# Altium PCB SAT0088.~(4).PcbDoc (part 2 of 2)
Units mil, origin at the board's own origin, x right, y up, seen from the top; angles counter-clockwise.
Board outline 1614.17 x 1181.1 mil, 4 copper layers (Top Layer, InternalPlane1, POWER, Bottom Layer), stack 59 mil thick; 84 components, 49 nets, 273 pads, 217 vias.
Unrouted connection lines stored in the file: 3.

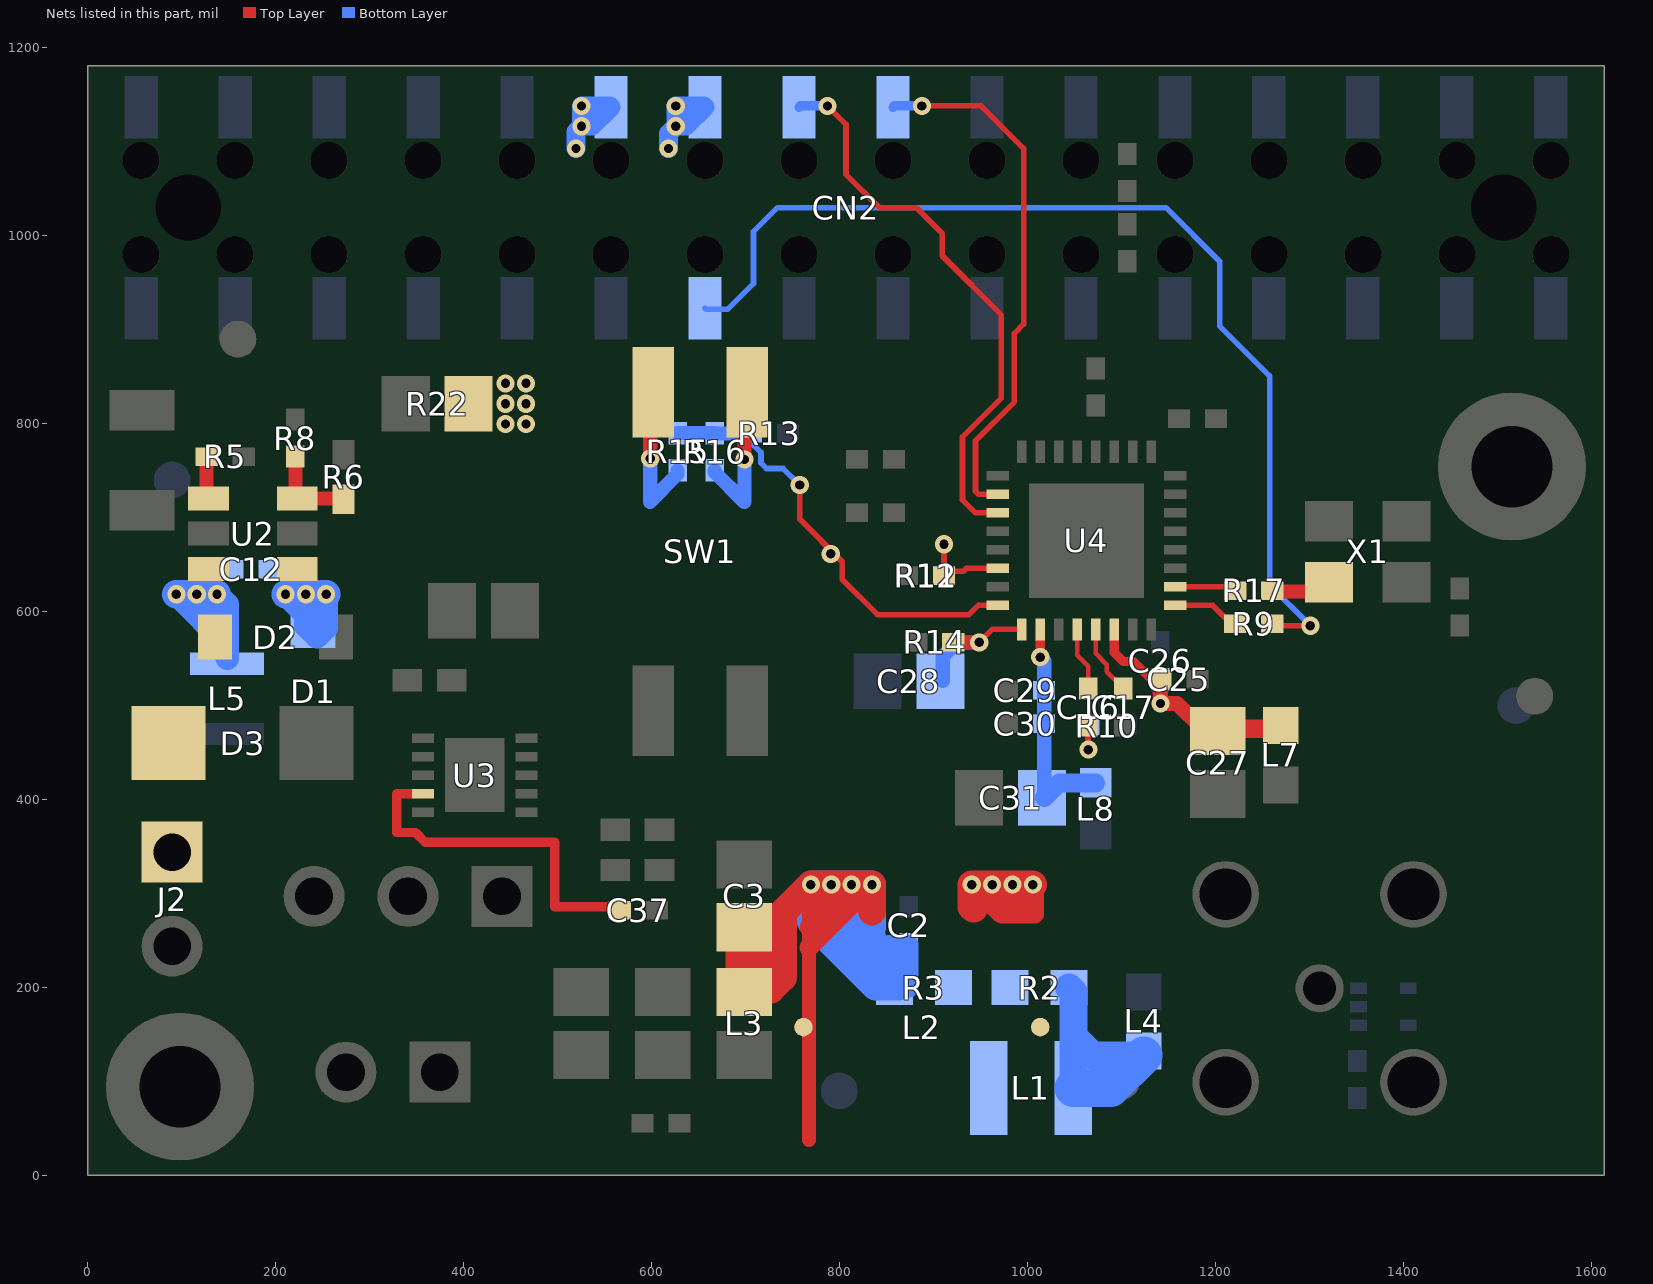
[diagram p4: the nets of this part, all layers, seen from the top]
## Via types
v1: diameter 19.29, hole 9.84, Top Layer to Bottom Layer, tented both sides, 208 vias
v2: diameter 19.68, hole 7.87, Top Layer to Bottom Layer, 5 vias
v3: diameter 19.68, hole 7.87, Top Layer to Bottom Layer, tented top, 4 vias

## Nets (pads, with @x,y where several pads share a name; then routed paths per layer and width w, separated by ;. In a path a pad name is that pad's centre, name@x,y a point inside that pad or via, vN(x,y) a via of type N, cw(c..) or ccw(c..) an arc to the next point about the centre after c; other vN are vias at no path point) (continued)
NetC2_1: C2.1 C3.1 L2.2 L3.1 R3.1 | length 1504.5
  Top Layer w15: 767.72,37.8 767.72,242.52 767.72,264.17 767.72,285.83 767.72,307.48 v1(769.68,309.45)
  Top Layer w20: 767.72,242.52 v1(834.65,309.45) ; 767.72,264.17 v1(812.99,309.45) ; 767.72,285.83 v1(791.34,309.45)
  Top Layer w30: L3.1@698.82,197.81 L3.1@726.94,197.81 ; v1@767.72,307.48 740.16,279.92 ; v1(769.68,309.45) v1(791.34,309.45) v1(812.99,309.45) v1(834.65,309.45) 834.65,281 ; L3.1@726.94,197.81 726.94,233.51 698.82,261.64 721.87,261.64 740.16,279.92 ; L3.1@726.94,197.81 740.16,211.02 740.16,279.92
  Top Layer w40: L3.1@698.82,197.81 C3.1@698.82,261.64
  Bottom Layer w20: 834.65,238.64 842.15,246.14 834.65,253.64 ; 852.39,220.9 874.02,242.52 C2.1@874.02,246.14 ; 852.68,246.14 C2.1@874.02,246.14 ; R3.1@874.07,199.21 874.07,246.08 C2.1@874.02,246.14
  Bottom Layer w30: 834.65,253.64 834.65,238.64 ; 834.65,264.17 v1(834.65,309.45) v1(812.99,309.45) ; 791.34,248.43 v1(791.34,309.45) ; 791.34,248.43 769.68,270.08 v1(769.68,309.45) v1(791.34,309.45) ; 791.34,248.43 838.58,201.18 862.69,201.18 867.4,205.89 852.39,220.9 834.65,238.64 ; v1(791.34,309.45) v1(812.99,309.45) ; v1(812.99,309.45) 812.99,260.3 834.65,238.64
NetC12_1: C12.1 D1.1 U2.1 | length 202
  Bottom Layer w25: v1(210.63,618.5) D1.1@232.28,596.85 ; v1(232.28,618.5) D1.1@232.28,596.85 ; v1(253.94,618.5) 253.94,583.07 D1.1@244.09,573.23 ; D1.1@232.28,596.85 232.28,585.04 D1.1@244.09,573.23 ; D1.1@232.28,596.85 244.09,585.04 D1.1@244.09,573.23
  Bottom Layer w30: v1(210.63,618.5) v1(232.28,618.5) v1(253.94,618.5)
NetC12_2: C12.2 D2.1 L5.1 U2.6 | length 241.7
  Top Layer w25: D2.1@137.8,571.26 D2.1@137.8,575.2
  Bottom Layer w25: v1(94.49,618.5) 148.43,564.57 ; v1(116.14,618.5) 148.43,586.22 ; v1(137.8,618.5) 148.43,607.87 148.43,586.22 ; L5.1@148.43,550.39 148.43,564.57 ; 148.43,564.57 148.43,586.22
  Bottom Layer w30: v1(94.49,618.5) v1(116.14,618.5) v1(137.8,618.5)
NetC16_1: C16.1 R10.1 | length 50.6
  Top Layer w6: v1(1064.96,453.15) C16.1@1064.96,478.43
  Bottom Layer w6: v1(1064.96,453.15) R10.1@1064.96,478.43
NetC16_2: C16.2 U4.12 | length 67.6
  Top Layer w5: U4.12@1053.15,581.1 1053.15,553.54 1064.96,541.73 C16.2@1064.96,518.43
NetC17_2: C17.2 U4.13 | length 74.9
  Top Layer w5: U4.13@1072.83,581.1 1072.83,555.51 1084.65,543.7 1084.65,536.14 C17.2@1102.36,518.43
NetC25_1: C25.1 C26.1 C27.1 L7.1 U4.14 | length 275.7
  Top Layer w9.84: U4.14@1092.52,581.1 1092.52,556.48 1102,547 1112.84,547 1131.89,527.95 C25.1@1141.42,527.95
  Top Layer w16: C25.1@1141.42,527.95 1141.42,502.68 v1(1141.73,502.36) 1159.45,502.36 1186.44,475.37 C27.1@1202.76,475.37
  Top Layer w20: C27.1@1202.76,475.37 1269.06,475.37 L7.1@1269.68,474.74
  Bottom Layer w15: v1(1141.73,502.36) C26.1@1141.73,527.64
NetC28_1: C28.1 R14.2 U4.9 | length 149.5
  Top Layer w6: v1(948.82,567.32) 962.6,581.1 U4.9@994.09,581.1
  Top Layer w15: R14.2@921.57,567.32 v1(948.82,567.32)
  Bottom Layer w15: C28.1@910.02,525.98 910.02,552.14 925.2,567.32 v1(948.82,567.32)
NetC29_1: C29.1 C30.1 C31.1 L8.1 U4.10 | length 242
  Top Layer w9.84: v1(1013.78,551.57) U4.10@1013.78,581.1
  Bottom Layer w15: v1(1013.78,551.57) 1018.03,547.32 1018.03,402.22 C31.1@1018.28,401.97
  Bottom Layer w20: C31.1@1018.28,401.97 1020.28,403.97 1033.97,417.66 L8.1@1072.83,417.72
NetC37_2: C37.2 U3.4 | length 376.9
  Top Layer w10: U3.4@355.88,406.31 329.31,406.31 329,406 329,365 349,365 359.31,354.69 494,354.69 ; 497,354.69 497,286 562.31,286 C37.2@566.31,282
NetCN2_19: CN2.19 CN2.21 R22.2 | length 239.4
  Bottom Layer w20: v1(519.68,1092.91) 519.68,1110.63 v1(525.59,1116.54) ; v1(618.11,1092.91) 618.11,1108.66 v1(625.98,1116.54) ; v1(525.59,1116.54) v1(525.59,1138.19) 555.82,1138.19 CN2.21@557.09,1136.92 536.7,1116.54 v1(525.59,1116.54) ; v1(625.98,1116.54) v1(625.98,1138.19) 655.82,1138.19 CN2.19@657.09,1136.92 636.7,1116.54 v1(625.98,1116.54)
  other v1: 444.88,799.61 466.54,799.61 444.88,821.26 466.54,821.26 444.88,842.91 466.54,842.91
NetD3_2: D3.2 J2.1 | length 5.3
  Top Layer w50: D3.2@86.26,460 D3.2@90,456.26
NetL1_1: L1.1 L2.1 R2.1 R3.2 | length 281.5
  Top Layer w20: v1(940.94,309.45) 951.77,298.62 972.44,277.95 994.09,277.95 ; v1(962.6,309.45) 994.09,277.95 ; v1(984.25,309.45) 995.08,298.62 1007.87,285.83 ; v1(1005.91,309.45) 1007.87,307.48 1007.87,285.83 ; 994.09,277.95 1007.87,277.95 1007.87,285.83
  Top Layer w30: 943,284 940.94,286.06 v1(940.94,309.45) v1(962.6,309.45) v1(984.25,309.45) v1(1005.91,309.45)
NetL1_2: L1.2 L4.1 R2.2 | length 281.3
  Bottom Layer w30: R2.2@1044.5,200 1049.21,195.28 1049.21,148.03 ; L1.2@1049.21,92.91 1049.21,148.03 ; L4.1@1124.02,127.78 1069.46,127.78 1049.21,148.03
  Bottom Layer w40: L1.2@1049.21,92.91 1088.58,92.91 L4.1@1124.02,127.78
NetR5_2: R5.2 U2.4 | length 45.4
  Top Layer w15: R5.2@126.46,764.96 126.46,720 U2.4@126.77,719.69
NetR6_1: R6.1 R8.1 U2.3 | length 95.3
  Top Layer w15: U2.3@221.26,719.69 221.26,764.65 R8.1@222.6,763.31 ; U2.3@223.24,720.4 R6.1@271.72,720.4
NetR9_2: R9.2 U4.17 | length 58.7
  Top Layer w6: U4.17@1157.48,606.69 1197.31,606.69 R9.2@1210.67,593.33
NetR11_2: R11.2 R12.1 U4.6 | length 127
  Top Layer w6: v1(911.42,671.65) 911.42,638.5 915.91,643 931.98,643 935.04,646.06 U4.6@968.5,646.06
  Bottom Layer w6: v1(911.42,671.65) 911.42,638.5 R12.1@911.73,638.19
NetR13_2: R13.2 R15.2 R16.1 U4.8 | length 469.4
  Top Layer w6: v1(757.87,734.65) 757.87,698.43 803.15,653.15 803.15,634.25 840.55,596.85 937.85,596.85 947.69,606.69 U4.8@968.5,606.69
  Bottom Layer w6: R13.2@705.59,789.76 705.59,779.65 706.31,779.65 716.65,769.31 716.65,758.16 722.44,752.36 740.16,752.36 v1(757.87,734.65)
  Bottom Layer w15: R15.2@627.95,790.08 667.32,790.08 667.64,789.76 R13.2@705.59,789.76
  other v1: 790.8,661.51
NetR15_1: R15.1 SW1.4 | length 158.9
  Top Layer w15: v1(598.82,763) SW1.4@598.82,830.31
  Bottom Layer w15: v1(598.82,763) 598.82,717.32 598.43,716.93 627.95,746.46 R15.1@627.95,750.08
NetR16_2: R16.2 SW1.3 | length 159.8
  Top Layer w15: v1(699,762) SW1.3@699,830.49
  Bottom Layer w15: R16.2@667.32,750.08 667.32,748.43 698.82,716.93 699,717.11 v1(699,762)
NetR17_2: R17.2 X1.3 | length 45
  Top Layer w15: R17.2@1259.91,621.38 X1.3@1304.87,621.38
OSC_48MHZ: R17.1 U4.18 | length 65.6
  Top Layer w6: U4.18@1157.48,626.38 1216.94,626.38 R17.1@1221.32,622
PCLK: CN2.17 U4.3 | length 610.1
  Top Layer w6: v1(787.4,1138.19) 807.09,1118.5 807.09,1065.35 842.52,1029.92 881.89,1029.92 909.45,1002.36 909.45,978.74 972.44,915.75 972.44,827.17 931.1,785.83 931.1,718.9 944.88,705.12 U4.3@968.5,705.12
  Bottom Layer w10: CN2.17@757.09,1136.92 758.35,1138.19 v1(787.4,1138.19)
VSYNC: CN2.15 U4.2 | length 569.2
  Top Layer w6: v1(887.8,1138.19) 950.79,1138.19 996.06,1092.91 996.06,905.91 986.22,896.06 986.22,823.23 944.88,781.89 944.88,728.12 948.2,724.8 U4.2@968.5,724.8
  Bottom Layer w10: CN2.15@857.09,1136.92 858.35,1138.19 v1(887.8,1138.19)
XCLK: CN2.20 R9.1 | length 1117.2
  Top Layer w6: R9.1@1260.68,585.04 v1(1301.18,585.04)
  Bottom Layer w6: CN2.20@657.09,922.92 658.35,921.65 681.1,921.65 708.66,949.21 708.66,1004.33 734.25,1029.92 1147.64,1029.92 1204.72,972.83 1204.72,903.94 1257.87,850.79 1257.87,628.35 v1(1301.18,585.04)
pads on no net: CN2. CN2.11 CN2.25 CN2.26 CN2.27 CN2.28 CN2.29 CN2.30 FID1.1 FID2.1 FID3.1 FID4.1 FID5.1 FID6.1 TR1.2 TR1.5 U3.5 U3.7 U3.8 U4.31 U4.32 X1.1
copper on no net: | length 74.3
  Bottom Layer w10: 332.68,513.86 368.43,513.86 395.67,486.61
  other v3: 412,398.44 392.32,426 431.68,426 412,453.56

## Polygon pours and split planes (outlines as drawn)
DGND on Top Layer "Top Layer, Top-DGND" (solid, remove dead copper, pour order 9): 27.56,25.98 1586.61,25.98 1586.61,1151.97 27.56,1151.97
+5V_EXT on Top Layer "Top Layer-No Net 1" (solid, remove dead copper, pour order 8): 205,495 205,265 285,265 285,500 205,500
NetD3_2 on Top Layer "Top Layer-No Net 1" (solid, remove dead copper, pour order 7): 45,500 45,310 125,310 125,500
DGND on Bottom Layer "Bottom Layer, Bottom-DGND" (solid, remove dead copper, pour order 10): 27.56,25.98 1586.61,25.98 1586.61,1151.97 27.56,1151.97
+3V3 on Bottom Layer "Top Layer-No Net 1" (solid, remove dead copper, pour order 6): 110,480 110,405 245,405 265,425 265,480
DGND on InternalPlane1 (split plane): 1594.08,20.1 20.1,20.1 20.1,1161.01 1594.08,1161.01
NetCN2_19 on POWER (split plane): 655.27,1043.94 507.87,1043.94 505.26,1043.6 502.83,1042.59 500.74,1040.99 499.14,1038.9 498.13,1036.47 497.79,1033.86 497.79,768.35 341.91,768.35 340.8,769.47 340.8,1161.57 655.27,1161.57
+5V on POWER (split plane): 320.62,780.59 320.31,780.9 320.62,780.9
+1V8 on POWER (split plane): 1092.28,774.02 1092.62,771.41 1093.63,768.97 1095.23,766.88 1097.32,765.28 1099.75,764.27 1102.36,763.93 1253.69,763.93 1253.69,557.48 1254.04,554.87 1255.04,552.44 1256.65,550.35 1258.74,548.75 1261.17,547.74 1263.78,547.39 1604.09,547.39 1604.09,10.09 1399.85,10.09 1399.85,317.32 1399.51,319.93 1398.5,322.37 1396.9,324.45 1394.81,326.06 1392.37,327.07 1389.76,327.41 1259.84,327.41 1257.23,327.07 1254.8,326.06 1252.71,324.45 1251.11,322.37 1250.1,319.93 1249.76,317.32 1249.76,276.23 491.1,276.23 491.1,352 490.71,353.95 489.6,355.6 487.95,356.71 486,357.1 393.11,357.1 387.1,363.11 387.1,383.52 389.02,384.99 390.62,387.08 391.63,389.52 391.98,392.13 391.98,654.74 506.73,654.74 509.9,651.57 509.9,454 509.9,401 510.29,399.05 511.4,397.4 513.05,396.29 515,395.9 516.95,396.29 517.87,396.9 560,396.9 561.95,397.29 563.6,398.4 564.71,400.05 565.1,402 565.1,653.89 565.95,654.74 770.83,654.74 772.4,652.71 774.48,651.11 776.92,650.1 779.53,649.76 782.14,650.1 784.57,651.11 786.66,652.71 788.26,654.8 789.27,657.23 789.61,659.84 789.61,669.44 842.52,669.44 845.13,669.78 847.56,670.79 849.65,672.4 851.25,674.48 852.26,676.92 852.61,679.53 852.61,821.26 852.26,823.87 851.25,826.3 849.65,828.39 847.56,829.99 845.13,831 842.52,831.35 807.09,831.35 804.48,831 802.76,830.29 802.04,829.99 799.95,828.39 773.38,801.82 750.24,801.82 750.24,858.42 1092.28,858.42
+3V3 on POWER (split plane): 1596.21,567.57 1273.87,567.57 1273.87,774.02 1273.52,776.63 1272.51,779.06 1270.91,781.15 1268.82,782.75 1266.39,783.76 1263.78,784.1 1112.45,784.1 1112.45,868.5 1112.1,871.11 1111.1,873.55 1109.49,875.64 1107.41,877.24 1104.97,878.25 1102.36,878.59 740.16,878.59 737.55,878.25 735.11,877.24 733.03,875.64 731.42,873.55 730.41,871.11 730.07,868.5 730.07,791.73 730.41,789.12 731.42,786.69 733.03,784.6 735.11,783 737.55,781.99 740.16,781.65 777.56,781.65 780.17,781.99 782.6,783 784.69,784.6 811.26,811.17 832.43,811.17 832.43,689.61 779.53,689.61 776.92,689.27 774.48,688.26 772.4,686.66 770.79,684.57 769.79,682.14 769.44,679.53 769.44,664.94 563.84,664.94 561.89,664.55 560.24,663.45 556.4,659.6 555.29,657.95 554.9,656 554.9,407.1 520.1,407.1 520.1,454 520.1,653.69 519.71,655.64 518.6,657.29 512.45,663.45 510.79,664.55 508.84,664.94 390.58,664.94 389.02,666.97 386.93,668.58 384.5,669.59 381.89,669.93 379.28,669.59 376.85,668.58 374.76,666.97 373.15,664.89 372.15,662.45 371.8,659.84 371.8,659.1 337.11,659.1 332.1,664.11 332.1,747.54 331.94,748.34 333.32,748.53 334.22,748.9 335.12,748.53 337.73,748.18 507.87,748.18 510.48,748.53 512.92,749.53 515.01,751.14 516.61,753.22 517.62,755.66 517.96,758.27 517.96,1023.77 665.35,1023.77 667.96,1024.12 670.4,1025.12 672.49,1026.73 674.09,1028.82 675.1,1031.25 675.44,1033.86 675.44,1161.57 1596.21,1161.57
+5V_LOCAL on POWER (split plane): 320.62,766.17 320.62,765.29 320.62,758.27 320.97,755.66 321.97,753.22 323.51,751.22 323.4,751.14 322.29,749.49 321.9,747.54 321.9,662 322.29,660.05 323.4,658.4 331.4,650.4 333.05,649.29 335,648.9 371.8,648.9 371.8,392.13 372.15,389.52 373.15,387.08 374.76,384.99 376.85,383.39 376.9,383.37 376.9,361 377.29,359.05 378.4,357.4 387.4,348.4 389.05,347.29 391,346.9 480.9,346.9 480.9,270.31 480.26,268.75 479.91,266.14 480.26,263.53 480.9,261.97 480.9,252.1 397.1,252.1 397.1,319 396.71,320.95 395.6,322.6 340.1,378.11 340.1,538 339.71,539.95 338.6,541.6 323.1,557.11 323.1,595 323.1,615 322.71,616.95 321.6,618.6 301.78,638.43 302.66,639.76 303.05,641.71 303.05,689.05 302.66,691 301.56,692.65 299.9,693.76 299.34,693.87 282.05,711.16 282.05,780.9 305.89,780.9
+5V on POWER (split plane): 320.62,791.1 276.95,791.1 275,790.71 273.35,789.6 272.24,787.95 271.85,786 271.85,709.05 272.24,707.1 273.35,705.44 292.85,685.94 292.85,641.71 292.99,641 292.4,640.6 291.29,638.95 290.9,637 291.29,635.05 292.4,633.4 312.9,612.89 312.9,595 312.9,555 313.29,553.05 314.4,551.4 329.9,535.89 329.9,376 330.29,374.05 331.4,372.4 386.9,316.89 386.9,256.1 296.11,256.1 293.1,259.11 293.1,347 292.71,348.95 291.6,350.6 233.75,408.46 234.09,411 234.09,873.91 320.62,873.91
+POC_VOLTAGE on POWER (split plane): 320.62,894.09 229,894.09 226.39,893.74 223.96,892.74 221.87,891.13 220.26,889.04 219.88,888.12 218.96,887.74 216.87,886.13 215.26,884.04 214.26,881.61 213.91,879 213.91,411 214.26,408.39 215.26,405.96 216.87,403.87 218.96,402.27 221.39,401.26 224,400.91 226.54,401.25 282.9,344.89 282.9,257 283.29,255.05 284.4,253.4 290.4,247.4 292.05,246.29 294,245.9 383.12,245.9 383.29,245.05 384.4,243.4 386.05,242.29 388,241.9 480.89,241.9 482.4,240.4 484.05,239.29 486,238.9 487.95,239.29 489.6,240.4 490.71,242.05 491.1,244 491.1,256.06 1259.84,256.06 1262.45,256.4 1264.89,257.41 1266.97,259.01 1268.58,261.1 1269.59,263.53 1269.93,266.14 1269.93,307.24 1379.68,307.24 1379.68,16.38 773.74,15.8 773.71,15.95 772.6,17.6 770.95,18.71 769,19.1 767.05,18.71 765.4,17.6 764.29,15.95 764.26,15.79 332.73,15.39 17.96,16.35 17.96,1161.57 320.62,1161.57

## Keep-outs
Keep-Out Layer:
  text ".Layer_Name" at 577,-858.49 h60

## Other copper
Top Layer:
  rectangle net +POC_VOLTAGE: 149,752 189,802
  rectangle net NetC12_2: 80.32,604.34 127,633
  rectangle net NetC12_2: 104,548 155,661
  rectangle net +POC_VOLTAGE: 494,57 558,156
  rectangle net +POC_VOLTAGE: 667,79 731,155
  rectangle net +POC_VOLTAGE: 580,79 644,156
  rectangle net NetCN2_19: 380,790 480,855
  rectangle net +5V: 265,790 365,855
  rectangle net NetC12_1: 200,605 265,655
  pour cut-out: 735,442 564,442 564,605 562,607 736,607
  pour cut-out: 491,354 613,354 610,495 492,496
  pour cut-out: 1338.58,602.76 1385.83,602.76 1385.83,740.55 1395.67,740.55 1385.83,750.39 1285.43,750.39 1261.81,726.77 1261.81,681.5 1338.58,681.5
  pour cut-out: 980.32,592.91 1145.67,592.91 1145.67,758.27 980.32,758.27
  pour cut-out: 27.56,793.7 27.56,726.77 106.3,726.77 106.3,793.7
  pour cut-out: 327,354 492,354 492,496 328,496
  pour cut-out: 848.43,20.08 927.17,20.08 927.17,293.7 848.43,293.7
  pour cut-out: 149.61,588.98 204.72,588.98 204.72,734.65 149.61,734.65
  pour cut-out: 477,148 649.61,148.03 649.61,179.53 477,179
  text ".Layer_Name" at 577,-858.49 h60
Bottom Layer:
  rectangle net NetC12_1: 182,604 220.13,655
  rectangle net NetC12_2: 127,604 166,655
  rectangle net NetL1_1: 930,40 981.5,200
  rectangle net NetL1_1: 901,179 1004,237
  rectangle net NetL1_1: 925,230 1018,325
  pour cut-out: 102.36,482.68 196.85,482.68 196.85,529.92 192.91,529.92 102.36,529.92
  text ".Layer_Name" at 577,-858.49 h60
InternalPlane1 (plane layer: these items are gaps in the copper):
  lines w20: 7.87,6.3 1606.3,6.3 1606.3,1171.65 7.87,1171.65 7.87,6.3
  text ".Layer_Name" at 567,-860.49 h60
POWER (plane layer: these items are gaps in the copper):
  lines w10: 11,773 12,774 ; 224,411 288,347 288,257 294,251 392,251 ; 224,879 229,884 ; 296,637 318,615 318,595 318,555 335,538 335,376 392,319 392,251 ; 296.95,689.05 276.95,709.05 276.95,786 308,786 ; 297.95,641.71 297.95,689.05 ; 326,768 331,763 308,786 ; 327,747.54 327,662 335,654 385,654 ; 333,786 308,786 ; 381.89,659.84 508.84,659.84 515,653.69 515,454 515,401 516,402 560,402 560,656 563.84,659.84 779.53,659.84 ; 382,387 382,361 391,352 486,352 486,244 483,247 388,247 392,251 ; 768,6 769,7 769,14
  lines w20: 224,411 224,879 ; 229,884 326,884 ; 330.71,758.27 330.71,1171.65 ; 332.7,5.3 1389.76,6.3 1389.76,317.32 1259.84,317.32 1259.84,266.14 1043.31,266.14 558.84,266.14 490,266.14 ; 337,5.29 7.87,6.3 7.87,1171.65 330.71,1171.65 ; 381.89,392.13 381.89,659.84 ; 779.53,659.84 779.53,679.53 842.52,679.53 842.52,821.26 807.09,821.26 777.56,791.73 740.16,791.73 740.16,868.5 1102.36,868.5 1102.36,774.02 1263.78,774.02 1263.78,557.48 1606.3,557.48 1606.3,1171.65 665.35,1171.65 ; 330.71,1171.65 330.71,765.29 337.73,758.27 ; 330.71,1171.65 665.35,1171.65 ; 337.73,758.27 507.87,758.27 ; 337.73,758.27 507.87,758.27 ; 507.87,758.27 507.87,1033.86 ; 507.87,758.27 507.87,1033.86 ; 507.87,1033.86 665.35,1033.86 ; 507.87,1033.86 665.35,1033.86 ; 665.35,1033.86 665.35,1171.65 ; 665.35,1033.86 665.35,1171.65
  text ".Layer_Name" at 569,-856.49 h60

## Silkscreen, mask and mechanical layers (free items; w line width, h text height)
Top Overlay:
  circle w5.91: c620.32,872.58 r23.42
  text "C" at 614,863 h18.75
  text "2014" at 662,855 h31.25
  text "+" at 150,330 h55
  text "-" at 155,230 h70
  text "EXT" at 210,210 h40
  text "+5V" at 310,210 h40
  text "5 Loc." at 410,210 h40
  text "-" at 265,170 h70
  text "+" at 370,170 h55
  text ".Layer_Name" at 577,-858.49 h60
Bottom Overlay:
  region: 1451.57,55.71 1539.07,55.71 1539.07,330.71 1451.57,330.71
  text "SAT0088" at 1490,455 h18.75 r90
  text "REV E1" at 1530,455 h18.75 r90
  text ".Layer_Name" at 577,-858.49 h60
Top Paste:
  text ".Layer_Name" at 577,-858.49 h60
Bottom Paste:
  text ".Layer_Name" at 577,-858.49 h60
Top Solder:
  text ".Layer_Name" at 577,-858.49 h60
  text ".Layer_Name" at 577,-858.49 h60
Bottom Solder:
  text ".Layer_Name" at 577,-858.49 h60
Drill Guide:
  text ".Layer_Name" at 577,-858.49 h60
M1 Board Outline:
  the board outline again, w10
  text ".Layer_Name" at 577,-858.49 h60
M2 Board Dimensions:
  rectangle: 124.5,-410.5 499.5,-285.5
  rectangle: -0.5,-285.5 124.5,-160.5
  lines w7: -0.5,-285.5 999.5,-285.5 ; 124.5,-410.5 124.5,-160.5 ; 249.5,-410.5 249.5,-160.5 ; 499.5,-410.5 499.5,-160.5 ; 749.5,-410.5 749.5,-160.5 ; -0.5,-410.5 -0.5,-160.5 999.5,-160.5 999.5,-410.5 -0.5,-410.5
  lines w10: -0.5,-475.5 -0.5,-455.5 ; 59.5,-485.5 -0.5,-465.5 ; 59.5,-445.5 -0.5,-465.5 ; 223.58,-465.5 -0.5,-465.5 ; 775.42,-465.5 999.5,-465.5 ; 939.5,-485.5 999.5,-465.5 ; 939.5,-445.5 999.5,-465.5 ; 999.5,-475.5 999.5,-455.5
  text "1000 (mil)" at 233.58,-501.49 h60
  text ".Layer_Name" at 577,-858.49 h60
M3 3D STEP Top:
  text ".Layer_Name" at 577,-858.49 h60
M4 3D STEP Bottom:
  text ".Layer_Name" at 577,-858.49 h60
M5 Assembly Top:
  lines w10: -292,-930.17 6308,-930.17 ; -292,-726.83 6310,-726.83 ; -292,-523.5 -292,-1133.5 3713,-1133.5 6310,-1133.5 6310,-523.5 -291.5,-523.5 -291.5,-1133.5 1284,-1133.5 ; 2173,-1133.5 2173,-523.5 ; 3440,-726.83 3440,-523.5 ; 4280,-726.83 4280,-523.5 ; 4902,-1140 4902,-937.17
  text "COMPONENTS MARKED 'DNP' SHOULD NOT BE POPULATED." at 1153.5,-318.5 h60
  text "ASSEMBLY VARIANT:" at 1153,-434 h60
  text ".VariantName" at 2189,-434 h60
  text "PCB VIEWED FROM TOP SIDE" at -228.5,-655.67 h60
  text "BOARD #:" at 2248,-655.67 h60
  text ".PRJ_Number" at 2793.5,-655.67 h60
  text "REV:" at 3638,-655.67 h60
  text ".PCB_Rev" at 3929.5,-655.67 h60
  text "SVN REV:" at 4476,-655.67 h60
  text ".VersionControl_RevNumber" at 4982,-655.67 h60
  text "IGNORE ->" at -228.5,-858.49 h60
  text "PLOT NAME =" at -228.5,-1064.34 h60
  text ".plot_File_Name" at 577,-1064.34 h60
  text "GENERATED    :" at 2250,-1064.34 h60
  text ".Print_Date" at 3119.5,-1064.34 h60
  text ".Print_Time" at 3848.5,-1064.34 h60
  text "TEXAS INSTRUMENTS" at 5113,-1064.34 h60
M6 Assembly Bottom:
  lines w10: -292.5,-727.33 6309.5,-727.33 ; -290.5,-930.67 6309.5,-930.67 ; 1115.5,-1140.5 1115.5,-937.67 ; 1737.5,-727.33 1737.5,-524 ; 2577.5,-727.33 2577.5,-524 ; 3844.5,-1134 3844.5,-524 ; 4733.5,-1134 6309,-1134 6309,-524 -292.5,-524 -292.5,-1134 2304.5,-1134 6309.5,-1134 6309.5,-524
  text "COMPONENTS MARKED 'DNP' SHOULD NOT BE POPULATED." at 6102,-318 h60
  text ".VariantName" at 5058,-434 h60
  text "ASSEMBLY VARIANT:" at 6097,-434 h60
  text ".VersionControl_RevNumber" at 1035.5,-656.17 h60
  text "SVN REV:" at 1541.5,-656.17 h60
  text ".PCB_Rev" at 2088,-656.17 h60
  text "REV:" at 2379.5,-656.17 h60
  text ".PRJ_Number" at 3224,-656.17 h60
  text "BOARD #:" at 3769.5,-656.17 h60
  text "PCB VIEWED FROM BOTTOM SIDE" at 6246,-656.17 h60
  text "IGNORE ->" at 2547.85,-858.49 h60
  text "TEXAS INSTRUMENTS" at 904.5,-1064.84 h60
  text ".Print_Time" at 2169,-1064.84 h60
  text ".Print_Date" at 2898,-1064.84 h60
  text "GENERATED    :" at 3767.5,-1064.84 h60
  text ".plot_File_Name" at 5440.5,-1064.84 h60
  text "PLOT NAME =" at 6246,-1064.84 h60
M9 Title Sheet:
  drawing of 57 lines, arcs and shapes, not listed
  text "1" at 739.84,8036.5 h70
  text "2" at 3235.5,8036.5 h70
  text "3" at 5724.84,8036.5 h70
  text "4" at 8231.51,8036.5 h70
  text "5" at 10730.5,8036.5 h70
  text "6" at 13235.5,8036.5 h70
  text "A" at -416.5,6893.5 h70
  text "A" at 14383.5,6893.5 h70
  text "B" at -416.5,4513.5 h70
  text "B" at 14383.5,4513.5 h70
  text "C" at -416.5,2138.5 h70
  text "C" at 14383.5,2138.5 h70
  text "PROJECT TITLE:" at 11343.5,277.5 h45
  text ".PRJ_Title" at 11393.5,144.17 h70
  text "DESIGNED FOR:" at 11343.5,-23.5 h45
  text ".PRJ_Customer" at 11393.5,-163.5 h70
  text "D" at -416.5,-231.5 h70
  text "D" at 14383.5,-231.5 h70
  text "FILE NAME:" at 11343.5,-323.5 h45
  text ".PCB_File_Name_No_Path" at 11393.5,-443.5 h70
  text "Texas Instruments (TI) and/or its licensors do not warrant the accuracy or completeness of this specification" at 6374,-605.34 h45
  text "ENGINEER:" at 11343.5,-613.5 h45
  text "CONVERSION BY:" at 12848.5,-613.5 h45
  text "or any information contained therein. TI and/or its licensors do not warrant that this design will meet" at 6329.01,-718 h45
  text ".PRJ_Engineer" at 11393.5,-768.49 h70
  text ".PCB_Layout" at 12899,-768.49 h70
  text "the specifications, will be suitable for your application or fit for any particular purpose, or will operate in" at 6329.01,-830.67 h45
  text ".Layer_Name" at 577,-858.49 h60
  text "ALTIUM DESIGNER VERSION:" at 12848.5,-923.5 h45
  text "an implementation. TI and/or its licensors do not warrant that the design is production worthy. You should" at 6329.01,-943.33 h45
  text "completely validate and test your design implementation to confirm the system functionality for your application." at 6374,-1056 h45
  text ".print_Scale" at 11393.5,-1056.83 h70
  text ".Application_BuildNumber" at 12899,-1056.83 h70
  text "1" at 739.84,-1263.5 h70
  text "2" at 3235.5,-1263.5 h70
  text "3" at 5724.84,-1263.5 h70
  text "4" at 8231.51,-1263.5 h70
  text "5" at 10730.5,-1263.5 h70
  text "6" at 13235.5,-1263.5 h70
M10 Fab Notes:
  drawing of 212 lines, arcs and shapes, not listed
  text "DESIGN INFORMATION" at 12381.02,6810 h60
  text "(REFER ALSO ARRAY/PANEL PROFILING INFORMATION)" at 12019.46,6648.29 h60
  text "BOARD SIZE" at 11333.46,6644 h60
  text "30mm" at 11795.78,6516.18 h60
  text "X" at 12301.46,6516.18 h60
  text "41mm" at 12532.78,6516.18 h60
  text "Number of Layers :" at 11736.46,6319 h60
  text "4" at 12831.27,6309 h60
  text "MIN. TRACK WIDTH:" at 11736.46,6180 h60
  text "5" at 12832.7,6180 h60
  text "MIL" at 12987.46,6180 h60
  text "MIN. CLEARANCE:" at 11736.46,6048 h60
  text "5" at 12832.7,6048 h60
  text "MIL" at 12987.46,6048 h60
  text "MIN. VIA PAD SIZE:" at 11736.46,5916 h60
  text "19" at 12802.71,5916 h60
  text "MIL" at 12987.46,5916 h60
  text "0.05mm (2MIL)" at 12431.46,5774.29 h60
  text "MINIMUM ANNULAR RING" at 11407.23,5770 h60
  text "EXTERNAL" at 13139.46,5770 h60
  text "PER" at 11607.23,5652 h60
  text "IPC-D-275 CLASS 2 LEVEL C" at 11827.23,5652 h60
  text "MIL, HOLES" at 13315.46,5539.71 h60
  text "+/-" at 12923,5539 h60
  text "+/-" at 13777,5539 h60
  text "REGISTRATION TOLERANCES:" at 11407.23,5534 h60
  text "METAL" at 12607,5534 h60
  text "5" at 13183.2,5534 h60
  text "3" at 14016.2,5534 h60
  text "MIL" at 14132.46,5534 h60
  text "MATERIAL:" at 11332.46,5324.54 h60
  text "FR-4 High Tg" at 12318.9,5184.21 h60
  text "FR-408" at 11753.46,5175.64 h60
  text "X" at 12165.46,5175.64 h60
  text "OTHER" at 13241.46,5175.64 h60
  text "62 MIL (1.6mm) +/-10%" at 12073.56,5012.92 h60
  text "THICKNESS:" at 11407.23,5008.64 h60
  text "X" at 11945.4,5008.64 h60
  text "OTHER" at 13358.46,5008.64 h60
  text "TOLERANCE:" at 11407.23,4850.64 h60
  text "X" at 12246.53,4850.64 h60
  text "ANSI IPC-6012 TYPE 3 CLASS 2" at 12433.48,4850.64 h60
  text "OTHER +/-" at 12433.46,4694.64 h60
  text "BOW & TWIST:" at 11407.23,4537.64 h60
  text "X" at 12246.53,4537.64 h60
  text "ANSI IPC-6012 TYPE 3 CLASS 2" at 12433.48,4537.64 h60
  text "OTHER +/-" at 12433.46,4379.13 h60
  text "COPPER THICKNESS (FINISHED):" at 11332.46,4243.64 h60
  text "1.4MIL (1oz)" at 12212.46,4090.92 h60
  text "2MIL (1.4oz)" at 12979.46,4090.92 h60
  text "2.8MIL (2oz)" at 13706.46,4090.92 h60
  text "OUTER:" at 11689.46,4086.64 h60
  text "X" at 12084,4086 h60
  text "1.4MIL (1oz)" at 12212.46,3933.92 h60
  text "2.8MIL (2oz)" at 12979.46,3933.92 h60
  text "N/A" at 13706,3934.29 h60
  text "INNER SIGNAL:" at 11400.38,3929.64 h60
  text "X" at 12085.42,3929.64 h60
  text "DRILLING:" at 11332.46,3790.64 h60
  text "REFERENCE:" at 11407.23,3673.64 h60
  text "X" at 12055.46,3673.64 h60
  text "AS SHOWN" at 12242.46,3673.64 h60
  text "X" at 12956.46,3673.64 h60
  text "NC_DRILL FILES" at 13093.46,3673.64 h60
  text "PTH MIN COPPER THICKNESS:" at 11407.23,3515.64 h60
  text "X" at 12757.46,3515.64 h60
  text "1MIL" at 12894.46,3515.64 h60
  text "OTHER" at 13391.46,3515.64 h60
  text "BOARD FINISH:" at 11332.46,3356.64 h60
  text "SILKSCREEN:" at 11487.68,3238.64 h60
  text "X" at 12436.46,3238.64 h60
  text "TOP" at 12562.46,3238.64 h60
  text "X" at 12946.46,3238.64 h60
  text "BOTTOM" at 13073.46,3238.64 h60
  text "SILKSCREEN COLOR:" at 11487.68,3071.64 h60
  text "X" at 12435.42,3071.64 h60
  text "WHITE" at 12562.46,3071.64 h60
  text "OTHER" at 13073.46,3071.64 h60
  text "SOLDER RESIST COLOR:" at 11487.68,2901.64 h60
  text "BLACK" at 13802.46,2752.44 h60
  text "GREEN" at 12182.46,2742.44 h60
  text "BLUE" at 12773.46,2742.44 h60
  text "OTHER" at 13311.46,2742.44 h60
  text "X" at 13160,2740 h60
  text "IMMERSION GOLD (ENIG)" at 12393.46,2553.92 h60
  text "ENEPIG" at 13731,2550.64 h60
  text "SURFACE FINISH:" at 11332.46,2549.64 h60
  text "X" at 12206.51,2549.64 h60
  text "IMM. TIN/SILVER OR EQUIV" at 11662,2392.64 h60
  text "OTHER" at 13093.46,2392.64 h60
  text "ARRAY/PANEL:" at 11332.46,2213.64 h60
  text "CUT AND TRIM PER MECH LAYER 1" at 12393.46,2209.35 h60
  text "N.C. ROUTE" at 12393.46,2057.64 h60
  text "X" at 13072.46,2057.64 h60
  text "V. SCORE" at 13259.46,2057.64 h60
  text "CERTIFICATION:" at 11332.46,1920.64 h60
  text "MATERIALS AND WORKMANSHIP FOR ALL PCBS" at 12057.46,1920.64 h60
  text "TO MEET OR EXCEED THE REQUIREMENTS OF:" at 12057.46,1822.64 h60
  text "X" at 11683.96,1686.13 h60
  text "ANSI IPC-A-600F CLASS ->" at 11822.96,1686.13 h60
  text "X" at 13462.02,1686.13 h60
  text "2" at 13580.96,1686.14 h60
  text "1" at 13265.96,1684.64 h60
  text "3" at 13934.96,1684.64 h60
  text "X" at 11686.02,1526.64 h60
  text "UL 94V-0" at 11822.96,1526.64 h60
  text "X" at 12498.02,1526.64 h60
  text "RoHS" at 12634.96,1526.64 h60
  text "OTHER" at 13279.36,1526.64 h60
  text "PER ORDER" at 13676.42,1526.64 h60
  text "ADDITIONAL REQUIREMENTS:" at 11332.46,1385.64 h60
  text "MICROSECTION:" at 11407.23,1270.64 h60
  text "YES" at 12312.96,1270.64 h60
  text "REQUIRED" at 13174.46,1114.49 h60
  text "BARE BOARD ELEC. TEST:" at 11407.23,1111.64 h60
  text "NONE" at 12712.96,1111.64 h60
  text "X" at 13047.46,1111.64 h60
  text "PER ORDER" at 13766.46,1111.64 h60
  text "MANUFACTURER'S UL:" at 11407.23,954.64 h60
  text "RAIL" at 12572.96,950.35 h60
  text "METAL" at 13064.77,950.35 h60
  text "X" at 13440,950 h60
  text "SILK" at 13576.46,950.35 h60
  text ".Layer_Name" at 577,-858.49 h60
M11 Gerber Information:
  lines w10: -292,-930.17 6308,-930.17 ; -292,-726.83 6310,-726.83 ; -292,-523.5 -292,-1133.5 3713,-1133.5 6310,-1133.5 6310,-523.5 -291.5,-523.5 -291.5,-1133.5 1284,-1133.5 ; 2173,-1133.5 2173,-523.5 ; 3440,-726.83 3440,-523.5 ; 4280,-726.83 4280,-523.5 ; 4902,-1140 4902,-937.17
  text "ALL ARTWORK VIEWED FROM TOP SIDE" at -228.5,-655.67 h60
  text "BOARD #:" at 2248,-655.67 h60
  text ".PRJ_Number" at 2793.5,-655.67 h60
  text "REV:" at 3638,-655.67 h60
  text ".PCB_Rev" at 3929.5,-655.67 h60
  text "SVN REV:" at 4476,-655.67 h60
  text ".VersionControl_RevNumber" at 4982,-655.67 h60
  text "LAYER NAME =" at -228.5,-858.49 h60
  text "PLOT NAME =" at -228.5,-1064.34 h60
  text ".plot_File_Name" at 577,-1064.34 h60
  text "GENERATED    :" at 2250,-1064.34 h60
  text ".Print_Date" at 3119.5,-1064.34 h60
  text ".Print_Time" at 3848.5,-1064.34 h60
  text "TEXAS INSTRUMENTS" at 5113,-1064.34 h60
M12 Stackup:
  lines w6: 9565,7698 14240,7698 ; 9565,7814.7 14240,7814.7 ; 9505,6962 ccw(c9543,6962) 9543,6924 14262,6924 ccw(c14262,6962) 14300,6962 14300,7914 ccw(c14262,7914) 14262,7952 9543,7952 ccw(c9543,7914) 9505,7914 9505,6962
  text "Layer Stack Up Detail for: SAT0088.PcbDoc" at 9565,7843.95 h53
  text "Layer" at 9565,7771.2 h27
  text "Gerber" at 10507.96,7771.2 h27
  text "Copper" at 11084.23,7771.2 h27
  text "Dielectric" at 11704.6,7771.2 h27
  text "Dielectric" at 12343.85,7771.2 h27
  text "Dielectric" at 13096.87,7771.2 h27
  text "Dielectric" at 13736.13,7771.2 h27
  text "Name" at 9565,7717.2 h27
  text "Document" at 10507.96,7717.2 h27
  text "Thickness" at 11084.23,7717.2 h27
  text "Height" at 11704.6,7717.2 h27
  text "Material" at 12343.85,7717.2 h27
  text "Constant" at 13096.87,7717.2 h27
  text "Type" at 13736.13,7717.2 h27
  text "Top Solder Mask" at 9565,7641.46 h38
  text "(.GTS)" at 10507.96,7641.46 h38
  text "0.4mil" at 11704.6,7641.46 h38
  text "Solder Resist" at 12343.85,7641.46 h38
  text "3.50" at 13096.87,7641.46 h38
  text "Top Layer" at 9565,7534.38 h38
  text "(.GTL)" at 10507.96,7534.38 h38
  text "1.4mil" at 11084.23,7534.38 h38
  text "5.2mil" at 11704.6,7480.83 h38
  text "370HR" at 12343.85,7480.83 h38
  text "4.80" at 13096.87,7480.83 h38
  text "PrePreg" at 13736.13,7480.83 h38
  text "InternalPlane1" at 9565,7427.29 h38
  text "(.GP1)" at 10507.96,7427.29 h38
  text "1.4mil" at 11084.23,7427.29 h38
  text "43mil" at 11704.6,7373.75 h38
  text "370HR" at 12343.85,7373.75 h38
  text "4.80" at 13096.87,7373.75 h38
  text "Core" at 13736.13,7373.75 h38
  text "POWER" at 9565,7320.21 h38
  text "(.GP2)" at 10507.96,7320.21 h38
  text "1.4mil" at 11084.23,7320.21 h38
  text "5.2mil" at 11704.6,7266.67 h38
  text "370HR" at 12343.85,7266.67 h38
  text "4.80" at 13096.87,7266.67 h38
  text "PrePreg" at 13736.13,7266.67 h38
  text "Bottom Layer" at 9565,7213.13 h38
  text "(.GBL)" at 10507.96,7213.13 h38
  text "1.4mil" at 11084.23,7213.13 h38
  text "Bottom Solder Mask" at 9565,7106.04 h38
  text "(.GBS)" at 10507.96,7106.04 h38
  text "0.4mil" at 11704.6,7106.04 h38
  text "Solder Resist" at 12343.85,7106.04 h38
  text "3.50" at 13096.87,7106.04 h38
  text ".Layer_Name" at 577,-858.49 h60
M13 Component Bodies Top:
  text ".Layer_Name" at 577,-858.49 h60
M14 Component Bodies Bottom:
  text ".Layer_Name" at 577,-858.49 h60
M15 Courtyards Top:
  text ".Layer_Name" at 577,-858.49 h60
M16 Courtyards Bottom:
  text ".Layer_Name" at 577,-858.49 h60
Drill Drawing:
  text ".legend" at 2239.5,509.5 h60
  text "Drill Table" at 2264.5,324.5 h60
  text ".Layer_Name" at 577,-858.49 h60

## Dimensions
0,0 to 1614.17,0 on M2 Board Dimensions
0,0 to 0,1181.1 on M2 Board Dimensions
